VERSION 5.4 ;
NAMESCASESENSITIVE ON ;
BUSBITCHARS "[]" ;
DIVIDERCHAR "/" ;
UNITS
  DATABASE MICRONS 2000 ;
END UNITS
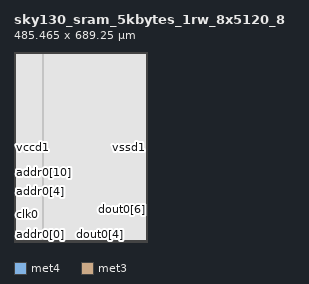
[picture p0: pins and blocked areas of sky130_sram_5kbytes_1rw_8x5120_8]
MACRO sky130_sram_5kbytes_1rw_8x5120_8
   CLASS BLOCK ;
   SIZE 485.465 BY 689.25 ;
   SYMMETRY X Y R90 ;
   PIN din0[0]
      DIRECTION INPUT ;
      PORT
         LAYER met4 ;
         RECT  105.06 0.0 105.44 0.38 ;
      END
   END din0[0]
   PIN din0[1]
      DIRECTION INPUT ;
      PORT
         LAYER met4 ;
         RECT  110.9 0.0 111.28 0.38 ;
      END
   END din0[1]
   PIN din0[2]
      DIRECTION INPUT ;
      PORT
         LAYER met4 ;
         RECT  116.74 0.0 117.12 0.38 ;
      END
   END din0[2]
   PIN din0[3]
      DIRECTION INPUT ;
      PORT
         LAYER met4 ;
         RECT  122.58 0.0 122.96 0.38 ;
      END
   END din0[3]
   PIN din0[4]
      DIRECTION INPUT ;
      PORT
         LAYER met4 ;
         RECT  128.42 0.0 128.8 0.38 ;
      END
   END din0[4]
   PIN din0[5]
      DIRECTION INPUT ;
      PORT
         LAYER met4 ;
         RECT  134.26 0.0 134.64 0.38 ;
      END
   END din0[5]
   PIN din0[6]
      DIRECTION INPUT ;
      PORT
         LAYER met4 ;
         RECT  140.1 0.0 140.48 0.38 ;
      END
   END din0[6]
   PIN din0[7]
      DIRECTION INPUT ;
      PORT
         LAYER met4 ;
         RECT  145.94 0.0 146.32 0.38 ;
      END
   END din0[7]
   PIN din0[8]
      DIRECTION INPUT ;
      PORT
         LAYER met4 ;
         RECT  151.78 0.0 152.16 0.38 ;
      END
   END din0[8]
   PIN addr0[0]
      DIRECTION INPUT ;
      PORT
         LAYER met4 ;
         RECT  81.7 0.0 82.08 0.38 ;
      END
   END addr0[0]
   PIN addr0[1]
      DIRECTION INPUT ;
      PORT
         LAYER met4 ;
         RECT  87.54 0.0 87.92 0.38 ;
      END
   END addr0[1]
   PIN addr0[2]
      DIRECTION INPUT ;
      PORT
         LAYER met4 ;
         RECT  93.38 0.0 93.76 0.38 ;
      END
   END addr0[2]
   PIN addr0[3]
      DIRECTION INPUT ;
      PORT
         LAYER met4 ;
         RECT  99.22 0.0 99.6 0.38 ;
      END
   END addr0[3]
   PIN addr0[4]
      DIRECTION INPUT ;
      PORT
         LAYER met3 ;
         RECT  0.0 210.21 0.38 210.59 ;
      END
   END addr0[4]
   PIN addr0[5]
      DIRECTION INPUT ;
      PORT
         LAYER met3 ;
         RECT  0.0 218.71 0.38 219.09 ;
      END
   END addr0[5]
   PIN addr0[6]
      DIRECTION INPUT ;
      PORT
         LAYER met3 ;
         RECT  0.0 224.35 0.38 224.73 ;
      END
   END addr0[6]
   PIN addr0[7]
      DIRECTION INPUT ;
      PORT
         LAYER met3 ;
         RECT  0.0 232.85 0.38 233.23 ;
      END
   END addr0[7]
   PIN addr0[8]
      DIRECTION INPUT ;
      PORT
         LAYER met3 ;
         RECT  0.0 238.49 0.38 238.87 ;
      END
   END addr0[8]
   PIN addr0[9]
      DIRECTION INPUT ;
      PORT
         LAYER met3 ;
         RECT  0.0 246.99 0.38 247.37 ;
      END
   END addr0[9]
   PIN addr0[10]
      DIRECTION INPUT ;
      PORT
         LAYER met3 ;
         RECT  0.0 252.385 0.38 252.765 ;
      END
   END addr0[10]
   PIN addr0[11]
      DIRECTION INPUT ;
      PORT
         LAYER met3 ;
         RECT  0.0 260.785 0.38 261.165 ;
      END
   END addr0[11]
   PIN addr0[12]
      DIRECTION INPUT ;
      PORT
         LAYER met3 ;
         RECT  0.0 266.77 0.38 267.15 ;
      END
   END addr0[12]
   PIN csb0
      DIRECTION INPUT ;
      PORT
         LAYER met3 ;
         RECT  0.0 100.55 0.38 100.93 ;
      END
   END csb0
   PIN web0
      DIRECTION INPUT ;
      PORT
         LAYER met3 ;
         RECT  0.0 109.05 0.38 109.43 ;
      END
   END web0
   PIN clk0
      DIRECTION INPUT ;
      PORT
         LAYER met3 ;
         RECT  0.0 101.24 0.38 101.62 ;
      END
   END clk0
   PIN spare_wen0
      DIRECTION INPUT ;
      PORT
         LAYER met4 ;
         RECT  157.62 0.0 158.0 0.38 ;
      END
   END spare_wen0
   PIN dout0[0]
      DIRECTION OUTPUT ;
      PORT
         LAYER met4 ;
         RECT  149.975 0.0 150.355 0.38 ;
      END
   END dout0[0]
   PIN dout0[1]
      DIRECTION OUTPUT ;
      PORT
         LAYER met4 ;
         RECT  190.69 0.0 191.07 0.38 ;
      END
   END dout0[1]
   PIN dout0[2]
      DIRECTION OUTPUT ;
      PORT
         LAYER met4 ;
         RECT  230.69 0.0 231.07 0.38 ;
      END
   END dout0[2]
   PIN dout0[3]
      DIRECTION OUTPUT ;
      PORT
         LAYER met4 ;
         RECT  270.69 0.0 271.07 0.38 ;
      END
   END dout0[3]
   PIN dout0[4]
      DIRECTION OUTPUT ;
      PORT
         LAYER met4 ;
         RECT  310.69 0.0 311.07 0.38 ;
      END
   END dout0[4]
   PIN dout0[5]
      DIRECTION OUTPUT ;
      PORT
         LAYER met4 ;
         RECT  350.69 0.0 351.07 0.38 ;
      END
   END dout0[5]
   PIN dout0[6]
      DIRECTION OUTPUT ;
      PORT
         LAYER met3 ;
         RECT  485.085 116.01 485.465 116.39 ;
      END
   END dout0[6]
   PIN dout0[7]
      DIRECTION OUTPUT ;
      PORT
         LAYER met3 ;
         RECT  485.085 117.5 485.465 117.88 ;
      END
   END dout0[7]
   PIN dout0[8]
      DIRECTION OUTPUT ;
      PORT
         LAYER met3 ;
         RECT  485.085 116.755 485.465 117.135 ;
      END
   END dout0[8]
   PIN vccd1
      DIRECTION INOUT ;
      USE POWER ; 
      SHAPE ABUTMENT ; 
      PORT
         LAYER met4 ;
         RECT  0.0 0.0 1.74 689.25 ;
         LAYER met4 ;
         RECT  483.725 0.0 485.465 689.25 ;
         LAYER met3 ;
         RECT  0.0 687.51 485.465 689.25 ;
         LAYER met3 ;
         RECT  0.0 0.0 485.465 1.74 ;
      END
   END vccd1
   PIN vssd1
      DIRECTION INOUT ;
      USE GROUND ; 
      SHAPE ABUTMENT ; 
      PORT
         LAYER met3 ;
         RECT  3.48 3.48 481.985 5.22 ;
         LAYER met3 ;
         RECT  3.48 684.03 481.985 685.77 ;
         LAYER met4 ;
         RECT  480.245 3.48 481.985 685.77 ;
         LAYER met4 ;
         RECT  3.48 3.48 5.22 685.77 ;
      END
   END vssd1
   OBS
   LAYER  met1 ;
      RECT  0.62 0.62 484.845 688.63 ;
   LAYER  met2 ;
      RECT  0.62 0.62 484.845 688.63 ;
   LAYER  met3 ;
      RECT  0.98 209.61 484.845 211.19 ;
      RECT  0.62 211.19 0.98 218.11 ;
      RECT  0.62 219.69 0.98 223.75 ;
      RECT  0.62 225.33 0.98 232.25 ;
      RECT  0.62 233.83 0.98 237.89 ;
      RECT  0.62 239.47 0.98 246.39 ;
      RECT  0.62 247.97 0.98 251.785 ;
      RECT  0.62 253.365 0.98 260.185 ;
      RECT  0.62 261.765 0.98 266.17 ;
      RECT  0.62 110.03 0.98 209.61 ;
      RECT  0.62 102.22 0.98 108.45 ;
      RECT  0.98 115.41 484.485 116.99 ;
      RECT  0.98 116.99 484.485 209.61 ;
      RECT  484.485 118.48 484.845 209.61 ;
      RECT  0.62 267.75 0.98 686.91 ;
      RECT  0.62 2.34 0.98 99.95 ;
      RECT  484.485 2.34 484.845 115.41 ;
      RECT  0.98 2.34 2.88 2.88 ;
      RECT  0.98 2.88 2.88 5.82 ;
      RECT  0.98 5.82 2.88 115.41 ;
      RECT  2.88 2.34 482.585 2.88 ;
      RECT  2.88 5.82 482.585 115.41 ;
      RECT  482.585 2.34 484.485 2.88 ;
      RECT  482.585 2.88 484.485 5.82 ;
      RECT  482.585 5.82 484.485 115.41 ;
      RECT  0.98 211.19 2.88 683.43 ;
      RECT  0.98 683.43 2.88 686.37 ;
      RECT  0.98 686.37 2.88 686.91 ;
      RECT  2.88 211.19 482.585 683.43 ;
      RECT  2.88 686.37 482.585 686.91 ;
      RECT  482.585 211.19 484.845 683.43 ;
      RECT  482.585 683.43 484.845 686.37 ;
      RECT  482.585 686.37 484.845 686.91 ;
   LAYER  met4 ;
      RECT  104.46 0.98 106.04 688.63 ;
      RECT  106.04 0.62 110.3 0.98 ;
      RECT  111.88 0.62 116.14 0.98 ;
      RECT  117.72 0.62 121.98 0.98 ;
      RECT  123.56 0.62 127.82 0.98 ;
      RECT  129.4 0.62 133.66 0.98 ;
      RECT  135.24 0.62 139.5 0.98 ;
      RECT  141.08 0.62 145.34 0.98 ;
      RECT  82.68 0.62 86.94 0.98 ;
      RECT  88.52 0.62 92.78 0.98 ;
      RECT  94.36 0.62 98.62 0.98 ;
      RECT  100.2 0.62 104.46 0.98 ;
      RECT  152.76 0.62 157.02 0.98 ;
      RECT  146.92 0.62 149.375 0.98 ;
      RECT  150.955 0.62 151.18 0.98 ;
      RECT  158.6 0.62 190.09 0.98 ;
      RECT  191.67 0.62 230.09 0.98 ;
      RECT  231.67 0.62 270.09 0.98 ;
      RECT  271.67 0.62 310.09 0.98 ;
      RECT  311.67 0.62 350.09 0.98 ;
      RECT  2.34 0.62 81.1 0.98 ;
      RECT  351.67 0.62 483.125 0.98 ;
      RECT  106.04 0.98 479.645 2.88 ;
      RECT  106.04 2.88 479.645 686.37 ;
      RECT  106.04 686.37 479.645 688.63 ;
      RECT  479.645 0.98 482.585 2.88 ;
      RECT  479.645 686.37 482.585 688.63 ;
      RECT  482.585 0.98 483.125 2.88 ;
      RECT  482.585 2.88 483.125 686.37 ;
      RECT  482.585 686.37 483.125 688.63 ;
      RECT  2.34 0.98 2.88 2.88 ;
      RECT  2.34 2.88 2.88 686.37 ;
      RECT  2.34 686.37 2.88 688.63 ;
      RECT  2.88 0.98 5.82 2.88 ;
      RECT  2.88 686.37 5.82 688.63 ;
      RECT  5.82 0.98 104.46 2.88 ;
      RECT  5.82 2.88 104.46 686.37 ;
      RECT  5.82 686.37 104.46 688.63 ;
   END
END    sky130_sram_5kbytes_1rw_8x5120_8
END    LIBRARY
